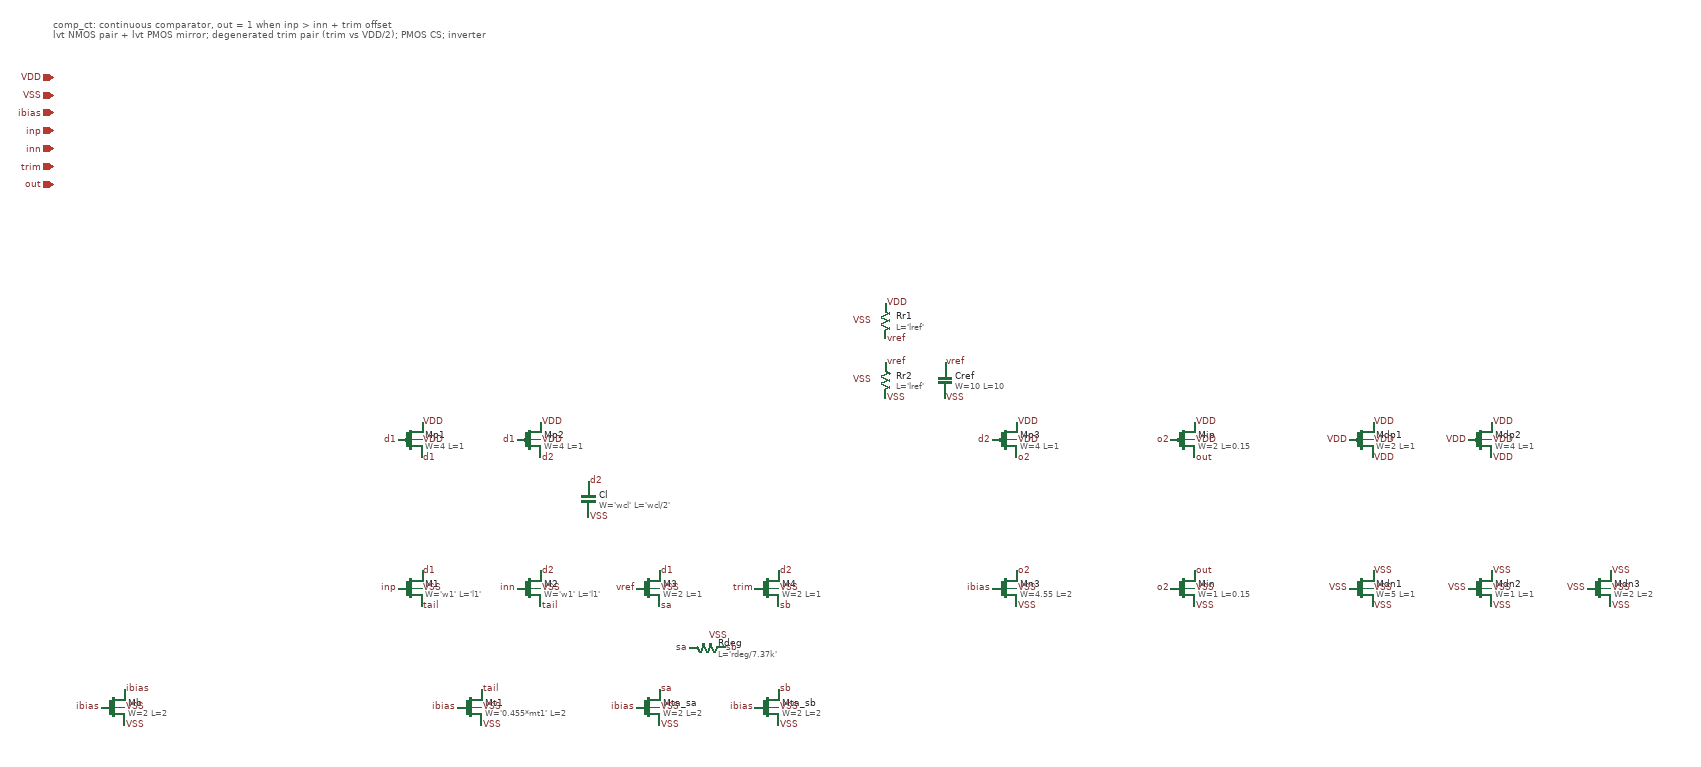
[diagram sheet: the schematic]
v {xschem version=3.4.5 file_version=1.2
}
G {}
K {}
V {}
S {}
E {}
T {comp_ct: continuous comparator, out = 1 when inp > inn + trim offset
lvt NMOS pair + lvt PMOS mirror; degenerated trim pair (trim vs VDD/2); PMOS CS; inverter} -700 -860 0 0 0.4 0.4 {}
C {devices/iopin.sym} -700 -760 0 0 {name=p1
lab=VDD}
C {devices/iopin.sym} -700 -730 0 0 {name=p2
lab=VSS}
C {devices/iopin.sym} -700 -700 0 0 {name=p3
lab=ibias}
C {devices/iopin.sym} -700 -670 0 0 {name=p4
lab=inp}
C {devices/iopin.sym} -700 -640 0 0 {name=p5
lab=inn}
C {devices/iopin.sym} -700 -610 0 0 {name=p6
lab=trim}
C {devices/iopin.sym} -700 -580 0 0 {name=p7
lab=out}
C {sky130_fd_pr/nfet_01v8.sym} -600 300 0 0 {name=Mb
nf=1
mult=1
ad="'int((nf+1)/2) * W/nf * 0.29'"
pd="'2*int((nf+1)/2) * (W/nf + 0.29)'"
as="'int((nf+2)/2) * W/nf * 0.29'"
ps="'2*int((nf+2)/2) * (W/nf + 0.29)'"
nrd="'0.29 / W'"
nrs="'0.29 / W'"
sa=0
sb=0
sd=0
L=2
W=2
model=nfet_01v8
spiceprefix=X}
C {devices/lab_pin.sym} -580 270 0 1 {name=p8
sig_type=std_logic
lab=ibias}
C {devices/lab_pin.sym} -620 300 0 0 {name=p9
sig_type=std_logic
lab=ibias}
C {devices/lab_pin.sym} -580 330 0 1 {name=p10
sig_type=std_logic
lab=VSS}
C {devices/lab_pin.sym} -580 300 0 1 {name=p11
sig_type=std_logic
lab=VSS}
C {sky130_fd_pr/nfet_01v8.sym} 0 300 0 0 {name=Mt1
nf=1
mult=4
ad="'int((nf+1)/2) * W/nf * 0.29'"
pd="'2*int((nf+1)/2) * (W/nf + 0.29)'"
as="'int((nf+2)/2) * W/nf * 0.29'"
ps="'2*int((nf+2)/2) * (W/nf + 0.29)'"
nrd="'0.29 / W'"
nrs="'0.29 / W'"
sa=0
sb=0
sd=0
L=2
W='0.455*mt1'
model=nfet_01v8
spiceprefix=X}
C {devices/lab_pin.sym} 20 270 0 1 {name=p12
sig_type=std_logic
lab=tail}
C {devices/lab_pin.sym} -20 300 0 0 {name=p13
sig_type=std_logic
lab=ibias}
C {devices/lab_pin.sym} 20 330 0 1 {name=p14
sig_type=std_logic
lab=VSS}
C {devices/lab_pin.sym} 20 300 0 1 {name=p15
sig_type=std_logic
lab=VSS}
C {sky130_fd_pr/nfet_01v8_lvt.sym} -100 100 0 0 {name=M1
nf=4
mult=1
ad="'int((nf+1)/2) * W/nf * 0.29'"
pd="'2*int((nf+1)/2) * (W/nf + 0.29)'"
as="'int((nf+2)/2) * W/nf * 0.29'"
ps="'2*int((nf+2)/2) * (W/nf + 0.29)'"
nrd="'0.29 / W'"
nrs="'0.29 / W'"
sa=0
sb=0
sd=0
L='l1'
W='w1'
model=nfet_01v8_lvt
spiceprefix=X}
C {devices/lab_pin.sym} -80 70 0 1 {name=p16
sig_type=std_logic
lab=d1}
C {devices/lab_pin.sym} -120 100 0 0 {name=p17
sig_type=std_logic
lab=inp}
C {devices/lab_pin.sym} -80 130 0 1 {name=p18
sig_type=std_logic
lab=tail}
C {devices/lab_pin.sym} -80 100 0 1 {name=p19
sig_type=std_logic
lab=VSS}
C {sky130_fd_pr/nfet_01v8_lvt.sym} 100 100 0 0 {name=M2
nf=4
mult=1
ad="'int((nf+1)/2) * W/nf * 0.29'"
pd="'2*int((nf+1)/2) * (W/nf + 0.29)'"
as="'int((nf+2)/2) * W/nf * 0.29'"
ps="'2*int((nf+2)/2) * (W/nf + 0.29)'"
nrd="'0.29 / W'"
nrs="'0.29 / W'"
sa=0
sb=0
sd=0
L='l1'
W='w1'
model=nfet_01v8_lvt
spiceprefix=X}
C {devices/lab_pin.sym} 120 70 0 1 {name=p20
sig_type=std_logic
lab=d2}
C {devices/lab_pin.sym} 80 100 0 0 {name=p21
sig_type=std_logic
lab=inn}
C {devices/lab_pin.sym} 120 130 0 1 {name=p22
sig_type=std_logic
lab=tail}
C {devices/lab_pin.sym} 120 100 0 1 {name=p23
sig_type=std_logic
lab=VSS}
C {sky130_fd_pr/pfet_01v8_lvt.sym} -100 -150 0 0 {name=Mp1
nf=1
mult=1
ad="'int((nf+1)/2) * W/nf * 0.29'"
pd="'2*int((nf+1)/2) * (W/nf + 0.29)'"
as="'int((nf+2)/2) * W/nf * 0.29'"
ps="'2*int((nf+2)/2) * (W/nf + 0.29)'"
nrd="'0.29 / W'"
nrs="'0.29 / W'"
sa=0
sb=0
sd=0
L=1
W=4
model=pfet_01v8_lvt
spiceprefix=X}
C {devices/lab_pin.sym} -80 -120 0 1 {name=p24
sig_type=std_logic
lab=d1}
C {devices/lab_pin.sym} -120 -150 0 0 {name=p25
sig_type=std_logic
lab=d1}
C {devices/lab_pin.sym} -80 -180 0 1 {name=p26
sig_type=std_logic
lab=VDD}
C {devices/lab_pin.sym} -80 -150 0 1 {name=p27
sig_type=std_logic
lab=VDD}
C {sky130_fd_pr/pfet_01v8_lvt.sym} 100 -150 0 0 {name=Mp2
nf=1
mult=1
ad="'int((nf+1)/2) * W/nf * 0.29'"
pd="'2*int((nf+1)/2) * (W/nf + 0.29)'"
as="'int((nf+2)/2) * W/nf * 0.29'"
ps="'2*int((nf+2)/2) * (W/nf + 0.29)'"
nrd="'0.29 / W'"
nrs="'0.29 / W'"
sa=0
sb=0
sd=0
L=1
W=4
model=pfet_01v8_lvt
spiceprefix=X}
C {devices/lab_pin.sym} 120 -120 0 1 {name=p28
sig_type=std_logic
lab=d2}
C {devices/lab_pin.sym} 80 -150 0 0 {name=p29
sig_type=std_logic
lab=d1}
C {devices/lab_pin.sym} 120 -180 0 1 {name=p30
sig_type=std_logic
lab=VDD}
C {devices/lab_pin.sym} 120 -150 0 1 {name=p31
sig_type=std_logic
lab=VDD}
C {sky130_fd_pr/nfet_01v8_lvt.sym} 300 100 0 0 {name=M3
nf=1
mult=1
ad="'int((nf+1)/2) * W/nf * 0.29'"
pd="'2*int((nf+1)/2) * (W/nf + 0.29)'"
as="'int((nf+2)/2) * W/nf * 0.29'"
ps="'2*int((nf+2)/2) * (W/nf + 0.29)'"
nrd="'0.29 / W'"
nrs="'0.29 / W'"
sa=0
sb=0
sd=0
L=1
W=2
model=nfet_01v8_lvt
spiceprefix=X}
C {devices/lab_pin.sym} 320 70 0 1 {name=p32
sig_type=std_logic
lab=d1}
C {devices/lab_pin.sym} 280 100 0 0 {name=p33
sig_type=std_logic
lab=vref}
C {devices/lab_pin.sym} 320 130 0 1 {name=p34
sig_type=std_logic
lab=sa}
C {devices/lab_pin.sym} 320 100 0 1 {name=p35
sig_type=std_logic
lab=VSS}
C {sky130_fd_pr/nfet_01v8.sym} 300 300 0 0 {name=Mta_sa
nf=1
mult='mta'
ad="'int((nf+1)/2) * W/nf * 0.29'"
pd="'2*int((nf+1)/2) * (W/nf + 0.29)'"
as="'int((nf+2)/2) * W/nf * 0.29'"
ps="'2*int((nf+2)/2) * (W/nf + 0.29)'"
nrd="'0.29 / W'"
nrs="'0.29 / W'"
sa=0
sb=0
sd=0
L=2
W=2
model=nfet_01v8
spiceprefix=X}
C {devices/lab_pin.sym} 320 270 0 1 {name=p36
sig_type=std_logic
lab=sa}
C {devices/lab_pin.sym} 280 300 0 0 {name=p37
sig_type=std_logic
lab=ibias}
C {devices/lab_pin.sym} 320 330 0 1 {name=p38
sig_type=std_logic
lab=VSS}
C {devices/lab_pin.sym} 320 300 0 1 {name=p39
sig_type=std_logic
lab=VSS}
C {sky130_fd_pr/nfet_01v8_lvt.sym} 500 100 0 0 {name=M4
nf=1
mult=1
ad="'int((nf+1)/2) * W/nf * 0.29'"
pd="'2*int((nf+1)/2) * (W/nf + 0.29)'"
as="'int((nf+2)/2) * W/nf * 0.29'"
ps="'2*int((nf+2)/2) * (W/nf + 0.29)'"
nrd="'0.29 / W'"
nrs="'0.29 / W'"
sa=0
sb=0
sd=0
L=1
W=2
model=nfet_01v8_lvt
spiceprefix=X}
C {devices/lab_pin.sym} 520 70 0 1 {name=p40
sig_type=std_logic
lab=d2}
C {devices/lab_pin.sym} 480 100 0 0 {name=p41
sig_type=std_logic
lab=trim}
C {devices/lab_pin.sym} 520 130 0 1 {name=p42
sig_type=std_logic
lab=sb}
C {devices/lab_pin.sym} 520 100 0 1 {name=p43
sig_type=std_logic
lab=VSS}
C {sky130_fd_pr/nfet_01v8.sym} 500 300 0 0 {name=Mta_sb
nf=1
mult='mta'
ad="'int((nf+1)/2) * W/nf * 0.29'"
pd="'2*int((nf+1)/2) * (W/nf + 0.29)'"
as="'int((nf+2)/2) * W/nf * 0.29'"
ps="'2*int((nf+2)/2) * (W/nf + 0.29)'"
nrd="'0.29 / W'"
nrs="'0.29 / W'"
sa=0
sb=0
sd=0
L=2
W=2
model=nfet_01v8
spiceprefix=X}
C {devices/lab_pin.sym} 520 270 0 1 {name=p44
sig_type=std_logic
lab=sb}
C {devices/lab_pin.sym} 480 300 0 0 {name=p45
sig_type=std_logic
lab=ibias}
C {devices/lab_pin.sym} 520 330 0 1 {name=p46
sig_type=std_logic
lab=VSS}
C {devices/lab_pin.sym} 520 300 0 1 {name=p47
sig_type=std_logic
lab=VSS}
C {sky130_fd_pr/res_xhigh_po_0p35.sym} 400 200 1 0 {name=Rdeg
L='rdeg/7.37k'
model=res_xhigh_po_0p35
mult=1
spiceprefix=X}
C {devices/lab_pin.sym} 430 200 0 1 {name=p48
sig_type=std_logic
lab=sb}
C {devices/lab_pin.sym} 370 200 0 0 {name=p49
sig_type=std_logic
lab=sa}
C {devices/lab_pin.sym} 400 180 0 1 {name=p50
sig_type=std_logic
lab=VSS}
C {sky130_fd_pr/res_xhigh_po_0p35.sym} 700 -350 0 0 {name=Rr1
L='lref'
model=res_xhigh_po_0p35
mult=1
spiceprefix=X}
C {devices/lab_pin.sym} 700 -380 0 1 {name=p51
sig_type=std_logic
lab=VDD}
C {devices/lab_pin.sym} 700 -320 0 1 {name=p52
sig_type=std_logic
lab=vref}
C {devices/lab_pin.sym} 680 -350 0 0 {name=p53
sig_type=std_logic
lab=VSS}
C {sky130_fd_pr/res_xhigh_po_0p35.sym} 700 -250 0 0 {name=Rr2
L='lref'
model=res_xhigh_po_0p35
mult=1
spiceprefix=X}
C {devices/lab_pin.sym} 700 -280 0 1 {name=p54
sig_type=std_logic
lab=vref}
C {devices/lab_pin.sym} 700 -220 0 1 {name=p55
sig_type=std_logic
lab=VSS}
C {devices/lab_pin.sym} 680 -250 0 0 {name=p56
sig_type=std_logic
lab=VSS}
C {sky130_fd_pr/cap_mim_m3_1.sym} 800 -250 0 0 {name=Cref
model=cap_mim_m3_1
W=10
L=10
MF=1
spiceprefix=X}
C {devices/lab_pin.sym} 800 -280 0 1 {name=p57
sig_type=std_logic
lab=vref}
C {devices/lab_pin.sym} 800 -220 0 1 {name=p58
sig_type=std_logic
lab=VSS}
C {sky130_fd_pr/cap_mim_m3_1.sym} 200 -50 0 0 {name=Cl
model=cap_mim_m3_1
W='wcl'
L='wcl/2'
MF=2
spiceprefix=X}
C {devices/lab_pin.sym} 200 -80 0 1 {name=p59
sig_type=std_logic
lab=d2}
C {devices/lab_pin.sym} 200 -20 0 1 {name=p60
sig_type=std_logic
lab=VSS}
C {sky130_fd_pr/pfet_01v8_lvt.sym} 900 -150 0 0 {name=Mp3
nf=1
mult=1
ad="'int((nf+1)/2) * W/nf * 0.29'"
pd="'2*int((nf+1)/2) * (W/nf + 0.29)'"
as="'int((nf+2)/2) * W/nf * 0.29'"
ps="'2*int((nf+2)/2) * (W/nf + 0.29)'"
nrd="'0.29 / W'"
nrs="'0.29 / W'"
sa=0
sb=0
sd=0
L=1
W=4
model=pfet_01v8_lvt
spiceprefix=X}
C {devices/lab_pin.sym} 920 -120 0 1 {name=p61
sig_type=std_logic
lab=o2}
C {devices/lab_pin.sym} 880 -150 0 0 {name=p62
sig_type=std_logic
lab=d2}
C {devices/lab_pin.sym} 920 -180 0 1 {name=p63
sig_type=std_logic
lab=VDD}
C {devices/lab_pin.sym} 920 -150 0 1 {name=p64
sig_type=std_logic
lab=VDD}
C {sky130_fd_pr/nfet_01v8.sym} 900 100 0 0 {name=Mn3
nf=1
mult=2
ad="'int((nf+1)/2) * W/nf * 0.29'"
pd="'2*int((nf+1)/2) * (W/nf + 0.29)'"
as="'int((nf+2)/2) * W/nf * 0.29'"
ps="'2*int((nf+2)/2) * (W/nf + 0.29)'"
nrd="'0.29 / W'"
nrs="'0.29 / W'"
sa=0
sb=0
sd=0
L=2
W=4.55
model=nfet_01v8
spiceprefix=X}
C {devices/lab_pin.sym} 920 70 0 1 {name=p65
sig_type=std_logic
lab=o2}
C {devices/lab_pin.sym} 880 100 0 0 {name=p66
sig_type=std_logic
lab=ibias}
C {devices/lab_pin.sym} 920 130 0 1 {name=p67
sig_type=std_logic
lab=VSS}
C {devices/lab_pin.sym} 920 100 0 1 {name=p68
sig_type=std_logic
lab=VSS}
C {sky130_fd_pr/pfet_01v8.sym} 1200 -150 0 0 {name=Mip
nf=1
mult=1
ad="'int((nf+1)/2) * W/nf * 0.29'"
pd="'2*int((nf+1)/2) * (W/nf + 0.29)'"
as="'int((nf+2)/2) * W/nf * 0.29'"
ps="'2*int((nf+2)/2) * (W/nf + 0.29)'"
nrd="'0.29 / W'"
nrs="'0.29 / W'"
sa=0
sb=0
sd=0
L=0.15
W=2
model=pfet_01v8
spiceprefix=X}
C {devices/lab_pin.sym} 1220 -120 0 1 {name=p69
sig_type=std_logic
lab=out}
C {devices/lab_pin.sym} 1180 -150 0 0 {name=p70
sig_type=std_logic
lab=o2}
C {devices/lab_pin.sym} 1220 -180 0 1 {name=p71
sig_type=std_logic
lab=VDD}
C {devices/lab_pin.sym} 1220 -150 0 1 {name=p72
sig_type=std_logic
lab=VDD}
C {sky130_fd_pr/nfet_01v8.sym} 1200 100 0 0 {name=Min
nf=1
mult=1
ad="'int((nf+1)/2) * W/nf * 0.29'"
pd="'2*int((nf+1)/2) * (W/nf + 0.29)'"
as="'int((nf+2)/2) * W/nf * 0.29'"
ps="'2*int((nf+2)/2) * (W/nf + 0.29)'"
nrd="'0.29 / W'"
nrs="'0.29 / W'"
sa=0
sb=0
sd=0
L=0.15
W=1
model=nfet_01v8
spiceprefix=X}
C {devices/lab_pin.sym} 1220 70 0 1 {name=p73
sig_type=std_logic
lab=out}
C {devices/lab_pin.sym} 1180 100 0 0 {name=p74
sig_type=std_logic
lab=o2}
C {devices/lab_pin.sym} 1220 130 0 1 {name=p75
sig_type=std_logic
lab=VSS}
C {devices/lab_pin.sym} 1220 100 0 1 {name=p76
sig_type=std_logic
lab=VSS}
C {sky130_fd_pr/nfet_01v8_lvt.sym} 1500 100 0 0 {name=Mdn1
nf=1
mult=2
ad="'int((nf+1)/2) * W/nf * 0.29'"
pd="'2*int((nf+1)/2) * (W/nf + 0.29)'"
as="'int((nf+2)/2) * W/nf * 0.29'"
ps="'2*int((nf+2)/2) * (W/nf + 0.29)'"
nrd="'0.29 / W'"
nrs="'0.29 / W'"
sa=0
sb=0
sd=0
L=1
W=5
model=nfet_01v8_lvt
spiceprefix=X}
C {devices/lab_pin.sym} 1520 70 0 1 {name=p77
sig_type=std_logic
lab=VSS}
C {devices/lab_pin.sym} 1480 100 0 0 {name=p78
sig_type=std_logic
lab=VSS}
C {devices/lab_pin.sym} 1520 130 0 1 {name=p79
sig_type=std_logic
lab=VSS}
C {devices/lab_pin.sym} 1520 100 0 1 {name=p80
sig_type=std_logic
lab=VSS}
C {sky130_fd_pr/nfet_01v8_lvt.sym} 1700 100 0 0 {name=Mdn2
nf=1
mult=2
ad="'int((nf+1)/2) * W/nf * 0.29'"
pd="'2*int((nf+1)/2) * (W/nf + 0.29)'"
as="'int((nf+2)/2) * W/nf * 0.29'"
ps="'2*int((nf+2)/2) * (W/nf + 0.29)'"
nrd="'0.29 / W'"
nrs="'0.29 / W'"
sa=0
sb=0
sd=0
L=1
W=1
model=nfet_01v8_lvt
spiceprefix=X}
C {devices/lab_pin.sym} 1720 70 0 1 {name=p81
sig_type=std_logic
lab=VSS}
C {devices/lab_pin.sym} 1680 100 0 0 {name=p82
sig_type=std_logic
lab=VSS}
C {devices/lab_pin.sym} 1720 130 0 1 {name=p83
sig_type=std_logic
lab=VSS}
C {devices/lab_pin.sym} 1720 100 0 1 {name=p84
sig_type=std_logic
lab=VSS}
C {sky130_fd_pr/nfet_01v8.sym} 1900 100 0 0 {name=Mdn3
nf=1
mult=1
ad="'int((nf+1)/2) * W/nf * 0.29'"
pd="'2*int((nf+1)/2) * (W/nf + 0.29)'"
as="'int((nf+2)/2) * W/nf * 0.29'"
ps="'2*int((nf+2)/2) * (W/nf + 0.29)'"
nrd="'0.29 / W'"
nrs="'0.29 / W'"
sa=0
sb=0
sd=0
L=2
W=2
model=nfet_01v8
spiceprefix=X}
C {devices/lab_pin.sym} 1920 70 0 1 {name=p85
sig_type=std_logic
lab=VSS}
C {devices/lab_pin.sym} 1880 100 0 0 {name=p86
sig_type=std_logic
lab=VSS}
C {devices/lab_pin.sym} 1920 130 0 1 {name=p87
sig_type=std_logic
lab=VSS}
C {devices/lab_pin.sym} 1920 100 0 1 {name=p88
sig_type=std_logic
lab=VSS}
C {sky130_fd_pr/pfet_01v8_lvt.sym} 1500 -150 0 0 {name=Mdp1
nf=1
mult=2
ad="'int((nf+1)/2) * W/nf * 0.29'"
pd="'2*int((nf+1)/2) * (W/nf + 0.29)'"
as="'int((nf+2)/2) * W/nf * 0.29'"
ps="'2*int((nf+2)/2) * (W/nf + 0.29)'"
nrd="'0.29 / W'"
nrs="'0.29 / W'"
sa=0
sb=0
sd=0
L=1
W=2
model=pfet_01v8_lvt
spiceprefix=X}
C {devices/lab_pin.sym} 1520 -120 0 1 {name=p89
sig_type=std_logic
lab=VDD}
C {devices/lab_pin.sym} 1480 -150 0 0 {name=p90
sig_type=std_logic
lab=VDD}
C {devices/lab_pin.sym} 1520 -180 0 1 {name=p91
sig_type=std_logic
lab=VDD}
C {devices/lab_pin.sym} 1520 -150 0 1 {name=p92
sig_type=std_logic
lab=VDD}
C {sky130_fd_pr/pfet_01v8_lvt.sym} 1700 -150 0 0 {name=Mdp2
nf=1
mult=1
ad="'int((nf+1)/2) * W/nf * 0.29'"
pd="'2*int((nf+1)/2) * (W/nf + 0.29)'"
as="'int((nf+2)/2) * W/nf * 0.29'"
ps="'2*int((nf+2)/2) * (W/nf + 0.29)'"
nrd="'0.29 / W'"
nrs="'0.29 / W'"
sa=0
sb=0
sd=0
L=1
W=4
model=pfet_01v8_lvt
spiceprefix=X}
C {devices/lab_pin.sym} 1720 -120 0 1 {name=p93
sig_type=std_logic
lab=VDD}
C {devices/lab_pin.sym} 1680 -150 0 0 {name=p94
sig_type=std_logic
lab=VDD}
C {devices/lab_pin.sym} 1720 -180 0 1 {name=p95
sig_type=std_logic
lab=VDD}
C {devices/lab_pin.sym} 1720 -150 0 1 {name=p96
sig_type=std_logic
lab=VDD}
